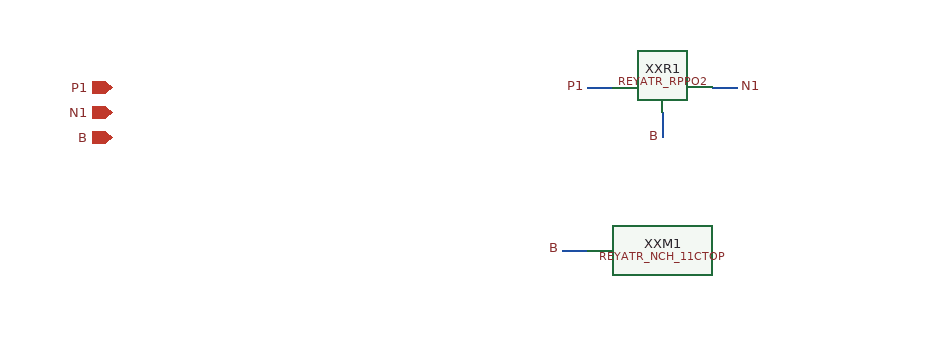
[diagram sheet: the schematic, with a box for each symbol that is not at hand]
v {xschem version=3.0.0 file_version=1.2 }
G {}
K {}
V {}
S {}
E {}
C {devices/iopin.sym} 0 0 0 0 {name=p0 lab=P1}
C {devices/iopin.sym} 0 20 0 0 {name=p1 lab=N1}
C {devices/iopin.sym} 0 40 0 0 {name=p2 lab=B}
C {LELO_TEMP_SKY130A/REYATR_RPPO2.sym} 400 0 0 0 {name=XXR1}
N 380.0 0.0 400.0 0.0 {lab=P1}
C {devices/lab_pin.sym} 380.0 0.0 0 0 {name=l0 sig_type=std_logic lab=P1 }
N 500.0 0.0 480.0 0.0 {lab=N1}
C {devices/lab_pin.sym} 500.0 0.0 2 0 {name=l1 sig_type=std_logic lab=N1 }
N 440.0 40.0 440.0 20.0 {lab=B}
C {devices/lab_pin.sym} 440.0 40.0 1 0 {name=l2 sig_type=std_logic lab=B }
C {LELO_TEMP_SKY130A/REYATR_NCH_11CTOP.sym} 400 130.0 0 0 {name=XXM1}
N 360.0 130.0 380.0 130.0 {lab=B}
C {devices/lab_pin.sym} 360.0 130.0 0 0 {name=l3 sig_type=std_logic lab=B }
